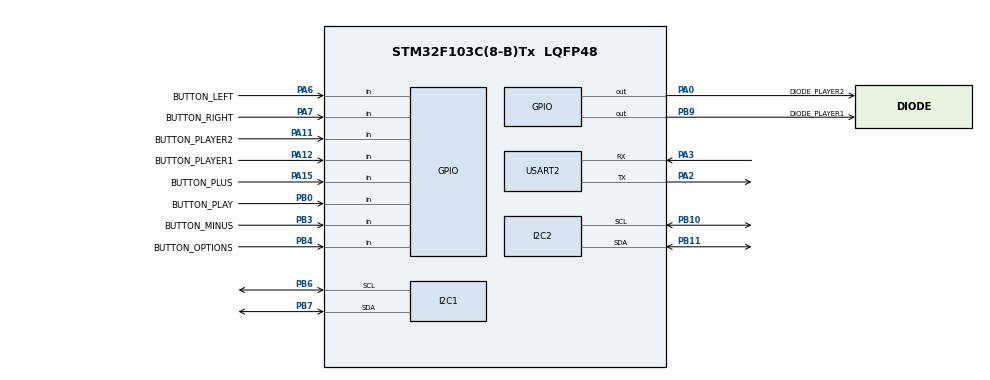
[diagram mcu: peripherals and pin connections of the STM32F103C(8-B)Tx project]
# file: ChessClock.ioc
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Dma.I2C1_TX.0.Direction=DMA_MEMORY_TO_PERIPH
Dma.I2C1_TX.0.Instance=DMA1_Channel6
Dma.I2C1_TX.0.MemDataAlignment=DMA_MDATAALIGN_BYTE
Dma.I2C1_TX.0.MemInc=DMA_MINC_ENABLE
Dma.I2C1_TX.0.Mode=DMA_NORMAL
Dma.I2C1_TX.0.PeriphDataAlignment=DMA_PDATAALIGN_BYTE
Dma.I2C1_TX.0.PeriphInc=DMA_PINC_DISABLE
Dma.I2C1_TX.0.Priority=DMA_PRIORITY_LOW
Dma.I2C2_TX.1.Direction=DMA_MEMORY_TO_PERIPH
Dma.I2C2_TX.1.Instance=DMA1_Channel4
Dma.I2C2_TX.1.MemDataAlignment=DMA_MDATAALIGN_BYTE
Dma.I2C2_TX.1.MemInc=DMA_MINC_ENABLE
Dma.I2C2_TX.1.Mode=DMA_NORMAL
Dma.I2C2_TX.1.PeriphDataAlignment=DMA_PDATAALIGN_BYTE
Dma.I2C2_TX.1.PeriphInc=DMA_PINC_DISABLE
Dma.I2C2_TX.1.Priority=DMA_PRIORITY_LOW
Dma.Request0=I2C1_TX
Dma.Request1=I2C2_TX
I2C1.I2C_Mode=I2C_Fast
I2C2.I2C_Mode=I2C_Fast
Mcu.Family=STM32F1
Mcu.Name=STM32F103C(8-B)Tx
Mcu.Package=LQFP48
NVIC.DMA1_Channel4_IRQn=true\:0\:0\:false\:false\:true\:false\:true\:true
NVIC.DMA1_Channel6_IRQn=true\:0\:0\:false\:false\:true\:false\:true\:true
NVIC.I2C1_EV_IRQn=true\:0\:0\:false\:false\:true\:true\:true\:true
NVIC.I2C2_EV_IRQn=true\:0\:0\:false\:false\:true\:true\:true\:true
NVIC.PriorityGroup=NVIC_PRIORITYGROUP_4
PA0-WKUP.GPIO_Label=DIODE_PLAYER2
PA0-WKUP.Signal=GPIO_Output
PA11.GPIO_Label=BUTTON_PLAYER2
PA11.GPIO_PuPd=GPIO_PULLUP
PA11.Signal=GPIO_Input
PA12.GPIO_Label=BUTTON_PLAYER1
PA12.GPIO_PuPd=GPIO_PULLUP
PA12.Signal=GPIO_Input
PA13.Mode=Serial_Wire
PA13.Signal=SYS_JTMS-SWDIO
PA14.Mode=Serial_Wire
PA14.Signal=SYS_JTCK-SWCLK
PA15.GPIO_Label=BUTTON_PLUS
PA15.GPIO_PuPd=GPIO_PULLUP
PA15.Signal=GPIO_Input
PA2.Mode=Asynchronous
PA2.Signal=USART2_TX
PA3.Mode=Asynchronous
PA3.Signal=USART2_RX
PA6.GPIO_Label=BUTTON_LEFT
PA6.GPIO_PuPd=GPIO_PULLUP
PA6.Signal=GPIO_Input
PA7.GPIO_Label=BUTTON_RIGHT
PA7.GPIO_PuPd=GPIO_PULLUP
PA7.Signal=GPIO_Input
PB0.GPIO_Label=BUTTON_PLAY
PB0.GPIO_PuPd=GPIO_PULLUP
PB0.Signal=GPIO_Input
PB10.Mode=I2C
PB10.Signal=I2C2_SCL
PB11.Mode=I2C
PB11.Signal=I2C2_SDA
PB3.GPIO_Label=BUTTON_MINUS
PB3.GPIO_PuPd=GPIO_PULLUP
PB3.Signal=GPIO_Input
PB4.GPIO_Label=BUTTON_OPTIONS
PB4.GPIO_PuPd=GPIO_PULLUP
PB4.Signal=GPIO_Input
PB6.Mode=I2C
PB6.Signal=I2C1_SCL
PB7.Mode=I2C
PB7.Signal=I2C1_SDA
PB9.GPIO_Label=DIODE_PLAYER1
PB9.Signal=GPIO_Output
PD0-OSC_IN.Mode=HSE-External-Oscillator
PD0-OSC_IN.Signal=RCC_OSC_IN
PD1-OSC_OUT.Mode=HSE-External-Oscillator
PD1-OSC_OUT.Signal=RCC_OSC_OUT
ProjectManager.HeapSize=0x200
ProjectManager.StackSize=0x400
ProjectManager.TargetToolchain=STM32CubeIDE
RCC.AHBFreq_Value=64000000
RCC.APB1CLKDivider=RCC_HCLK_DIV2
RCC.APB1Freq_Value=32000000
RCC.APB1TimFreq_Value=64000000
RCC.APB2Freq_Value=64000000
RCC.APB2TimFreq_Value=64000000
RCC.HCLKFreq_Value=64000000
RCC.PLLMUL=RCC_PLL_MUL8
RCC.PLLSourceVirtual=RCC_PLLSOURCE_HSE
RCC.SYSCLKFreq_VALUE=64000000
RCC.SYSCLKSource=RCC_SYSCLKSOURCE_PLLCLK
RCC.USBFreq_Value=64000000
USART2.VirtualMode=VM_ASYNC
VP_TIM4_VS_ClockSourceINT.Mode=Internal
board=custom

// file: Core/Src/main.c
/* USER CODE BEGIN Header */
/**
  ******************************************************************************
  * @file           : main.c
  * @brief          : Main program body
  ******************************************************************************
  * @attention
  *
  * Copyright (c) 2022 STMicroelectronics.
  * All rights reserved.
  *
  * This software is licensed under terms that can be found in the LICENSE file
  * in the root directory of this software component.
  * If no LICENSE file comes with this software, it is provided AS-IS.
  *
  ******************************************************************************
  */
/* USER CODE END Header */
#include "main.h"
#include "dma.h"
#include "i2c.h"
#include "tim.h"
#include "usart.h"
#include "gpio.h"

void SystemClock_Config(void);

int main(void)
{

  /* MCU Configuration--------------------------------------------------------*/

  /* Reset of all peripherals, Initializes the Flash interface and the Systick. */
  HAL_Init();

  /* Configure the system clock */
  SystemClock_Config();

  /* Initialize all configured peripherals */
  MX_GPIO_Init();
  MX_DMA_Init();
  MX_I2C1_Init();
  MX_USART2_UART_Init();
  MX_I2C2_Init();
  MX_TIM4_Init();

  /* Infinite loop */
  while (1)
  {

  }
}

void SystemClock_Config(void)
{
  RCC_OscInitTypeDef RCC_OscInitStruct = {0};
  RCC_ClkInitTypeDef RCC_ClkInitStruct = {0};

  /** Initializes the RCC Oscillators according to the specified parameters
  * in the RCC_OscInitTypeDef structure.
  */
  RCC_OscInitStruct.OscillatorType = RCC_OSCILLATORTYPE_HSI;
  RCC_OscInitStruct.HSIState = RCC_HSI_ON;
  RCC_OscInitStruct.HSICalibrationValue = RCC_HSICALIBRATION_DEFAULT;
  RCC_OscInitStruct.PLL.PLLState = RCC_PLL_ON;
  RCC_OscInitStruct.PLL.PLLSource = RCC_PLLSOURCE_HSI_DIV2;
  RCC_OscInitStruct.PLL.PLLMUL = RCC_PLL_MUL4;
  if (HAL_RCC_OscConfig(&RCC_OscInitStruct) != HAL_OK)
  {
    Error_Handler();
  }

  /** Initializes the CPU, AHB and APB buses clocks
  */
  RCC_ClkInitStruct.ClockType = RCC_CLOCKTYPE_HCLK|RCC_CLOCKTYPE_SYSCLK
                              |RCC_CLOCKTYPE_PCLK1|RCC_CLOCKTYPE_PCLK2;
  RCC_ClkInitStruct.SYSCLKSource = RCC_SYSCLKSOURCE_PLLCLK;
  RCC_ClkInitStruct.AHBCLKDivider = RCC_SYSCLK_DIV1;
  RCC_ClkInitStruct.APB1CLKDivider = RCC_HCLK_DIV1;
  RCC_ClkInitStruct.APB2CLKDivider = RCC_HCLK_DIV1;

  if (HAL_RCC_ClockConfig(&RCC_ClkInitStruct, FLASH_LATENCY_0) != HAL_OK)
  {
    Error_Handler();
  }
}

void Error_Handler(void)
{
  __disable_irq();
  while (1)
  {
  }
}
